VERSION 5.7 ;
  NOWIREEXTENSIONATPIN ON ;
  DIVIDERCHAR "/" ;
  BUSBITCHARS "[]" ;
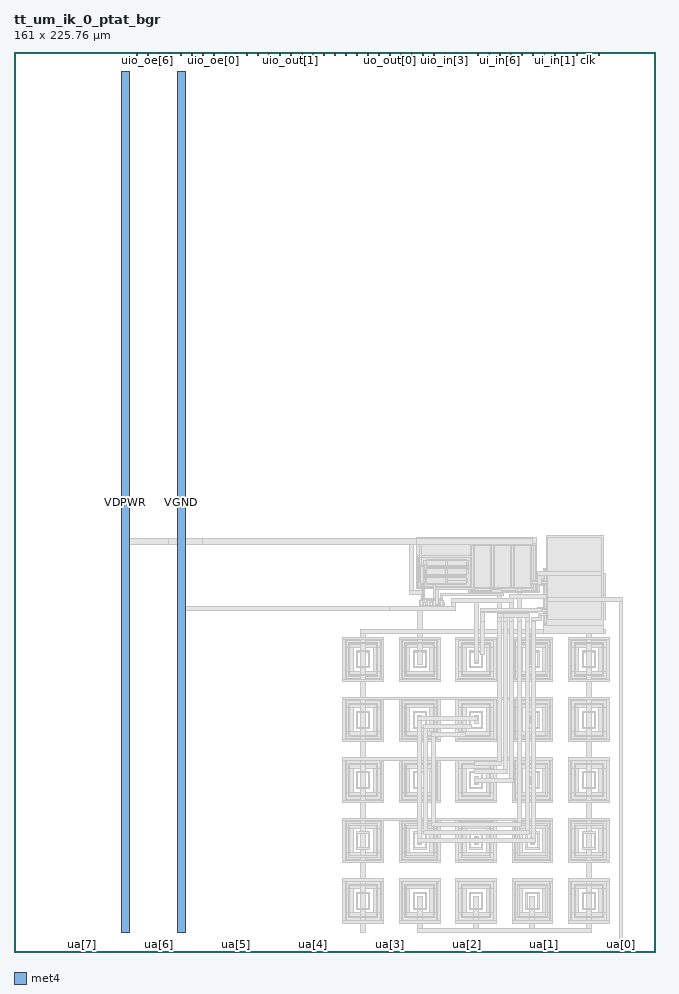
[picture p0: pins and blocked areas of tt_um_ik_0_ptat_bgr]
MACRO tt_um_ik_0_ptat_bgr
  CLASS BLOCK ;
  FOREIGN tt_um_ik_0_ptat_bgr ;
  ORIGIN 0.000 0.000 ;
  SIZE 161.000 BY 225.760 ;
  PIN clk
    DIRECTION INPUT ;
    USE SIGNAL ;
    PORT
      LAYER met4 ;
        RECT 143.830 224.760 144.130 225.760 ;
    END
  END clk
  PIN ena
    DIRECTION INPUT ;
    USE SIGNAL ;
    PORT
      LAYER met4 ;
        RECT 146.590 224.760 146.890 225.760 ;
    END
  END ena
  PIN rst_n
    DIRECTION INPUT ;
    USE SIGNAL ;
    PORT
      LAYER met4 ;
        RECT 141.070 224.760 141.370 225.760 ;
    END
  END rst_n
  PIN ua[0]
    DIRECTION INOUT ;
    USE SIGNAL ;
    ANTENNAGATEAREA 0.500000 ;
    ANTENNADIFFAREA 2.900000 ;
    PORT
      LAYER met4 ;
        RECT 151.810 0.000 152.710 1.000 ;
    END
  END ua[0]
  PIN ua[1]
    DIRECTION INOUT ;
    USE SIGNAL ;
    PORT
      LAYER met4 ;
        RECT 132.490 0.000 133.390 1.000 ;
    END
  END ua[1]
  PIN ua[2]
    DIRECTION INOUT ;
    USE SIGNAL ;
    PORT
      LAYER met4 ;
        RECT 113.170 0.000 114.070 1.000 ;
    END
  END ua[2]
  PIN ua[3]
    DIRECTION INOUT ;
    USE SIGNAL ;
    PORT
      LAYER met4 ;
        RECT 93.850 0.000 94.750 1.000 ;
    END
  END ua[3]
  PIN ua[4]
    DIRECTION INOUT ;
    USE SIGNAL ;
    PORT
      LAYER met4 ;
        RECT 74.530 0.000 75.430 1.000 ;
    END
  END ua[4]
  PIN ua[5]
    DIRECTION INOUT ;
    USE SIGNAL ;
    PORT
      LAYER met4 ;
        RECT 55.210 0.000 56.110 1.000 ;
    END
  END ua[5]
  PIN ua[6]
    DIRECTION INOUT ;
    USE SIGNAL ;
    PORT
      LAYER met4 ;
        RECT 35.890 0.000 36.790 1.000 ;
    END
  END ua[6]
  PIN ua[7]
    DIRECTION INOUT ;
    USE SIGNAL ;
    PORT
      LAYER met4 ;
        RECT 16.570 0.000 17.470 1.000 ;
    END
  END ua[7]
  PIN ui_in[0]
    DIRECTION INPUT ;
    USE SIGNAL ;
    PORT
      LAYER met4 ;
        RECT 138.310 224.760 138.610 225.760 ;
    END
  END ui_in[0]
  PIN ui_in[1]
    DIRECTION INPUT ;
    USE SIGNAL ;
    PORT
      LAYER met4 ;
        RECT 135.550 224.760 135.850 225.760 ;
    END
  END ui_in[1]
  PIN ui_in[2]
    DIRECTION INPUT ;
    USE SIGNAL ;
    PORT
      LAYER met4 ;
        RECT 132.790 224.760 133.090 225.760 ;
    END
  END ui_in[2]
  PIN ui_in[3]
    DIRECTION INPUT ;
    USE SIGNAL ;
    PORT
      LAYER met4 ;
        RECT 130.030 224.760 130.330 225.760 ;
    END
  END ui_in[3]
  PIN ui_in[4]
    DIRECTION INPUT ;
    USE SIGNAL ;
    PORT
      LAYER met4 ;
        RECT 127.270 224.760 127.570 225.760 ;
    END
  END ui_in[4]
  PIN ui_in[5]
    DIRECTION INPUT ;
    USE SIGNAL ;
    PORT
      LAYER met4 ;
        RECT 124.510 224.760 124.810 225.760 ;
    END
  END ui_in[5]
  PIN ui_in[6]
    DIRECTION INPUT ;
    USE SIGNAL ;
    PORT
      LAYER met4 ;
        RECT 121.750 224.760 122.050 225.760 ;
    END
  END ui_in[6]
  PIN ui_in[7]
    DIRECTION INPUT ;
    USE SIGNAL ;
    PORT
      LAYER met4 ;
        RECT 118.990 224.760 119.290 225.760 ;
    END
  END ui_in[7]
  PIN uio_in[0]
    DIRECTION INPUT ;
    USE SIGNAL ;
    PORT
      LAYER met4 ;
        RECT 116.230 224.760 116.530 225.760 ;
    END
  END uio_in[0]
  PIN uio_in[1]
    DIRECTION INPUT ;
    USE SIGNAL ;
    PORT
      LAYER met4 ;
        RECT 113.470 224.760 113.770 225.760 ;
    END
  END uio_in[1]
  PIN uio_in[2]
    DIRECTION INPUT ;
    USE SIGNAL ;
    PORT
      LAYER met4 ;
        RECT 110.710 224.760 111.010 225.760 ;
    END
  END uio_in[2]
  PIN uio_in[3]
    DIRECTION INPUT ;
    USE SIGNAL ;
    PORT
      LAYER met4 ;
        RECT 107.950 224.760 108.250 225.760 ;
    END
  END uio_in[3]
  PIN uio_in[4]
    DIRECTION INPUT ;
    USE SIGNAL ;
    PORT
      LAYER met4 ;
        RECT 105.190 224.760 105.490 225.760 ;
    END
  END uio_in[4]
  PIN uio_in[5]
    DIRECTION INPUT ;
    USE SIGNAL ;
    PORT
      LAYER met4 ;
        RECT 102.430 224.760 102.730 225.760 ;
    END
  END uio_in[5]
  PIN uio_in[6]
    DIRECTION INPUT ;
    USE SIGNAL ;
    PORT
      LAYER met4 ;
        RECT 99.670 224.760 99.970 225.760 ;
    END
  END uio_in[6]
  PIN uio_in[7]
    DIRECTION INPUT ;
    USE SIGNAL ;
    PORT
      LAYER met4 ;
        RECT 96.910 224.760 97.210 225.760 ;
    END
  END uio_in[7]
  PIN uio_oe[0]
    DIRECTION OUTPUT ;
    USE SIGNAL ;
    PORT
      LAYER met4 ;
        RECT 49.990 224.760 50.290 225.760 ;
    END
  END uio_oe[0]
  PIN uio_oe[1]
    DIRECTION OUTPUT ;
    USE SIGNAL ;
    PORT
      LAYER met4 ;
        RECT 47.230 224.760 47.530 225.760 ;
    END
  END uio_oe[1]
  PIN uio_oe[2]
    DIRECTION OUTPUT ;
    USE SIGNAL ;
    PORT
      LAYER met4 ;
        RECT 44.470 224.760 44.770 225.760 ;
    END
  END uio_oe[2]
  PIN uio_oe[3]
    DIRECTION OUTPUT ;
    USE SIGNAL ;
    PORT
      LAYER met4 ;
        RECT 41.710 224.760 42.010 225.760 ;
    END
  END uio_oe[3]
  PIN uio_oe[4]
    DIRECTION OUTPUT ;
    USE SIGNAL ;
    PORT
      LAYER met4 ;
        RECT 38.950 224.760 39.250 225.760 ;
    END
  END uio_oe[4]
  PIN uio_oe[5]
    DIRECTION OUTPUT ;
    USE SIGNAL ;
    PORT
      LAYER met4 ;
        RECT 36.190 224.760 36.490 225.760 ;
    END
  END uio_oe[5]
  PIN uio_oe[6]
    DIRECTION OUTPUT ;
    USE SIGNAL ;
    PORT
      LAYER met4 ;
        RECT 33.430 224.760 33.730 225.760 ;
    END
  END uio_oe[6]
  PIN uio_oe[7]
    DIRECTION OUTPUT ;
    USE SIGNAL ;
    PORT
      LAYER met4 ;
        RECT 30.670 224.760 30.970 225.760 ;
    END
  END uio_oe[7]
  PIN uio_out[0]
    DIRECTION OUTPUT ;
    USE SIGNAL ;
    PORT
      LAYER met4 ;
        RECT 72.070 224.760 72.370 225.760 ;
    END
  END uio_out[0]
  PIN uio_out[1]
    DIRECTION OUTPUT ;
    USE SIGNAL ;
    PORT
      LAYER met4 ;
        RECT 69.310 224.760 69.610 225.760 ;
    END
  END uio_out[1]
  PIN uio_out[2]
    DIRECTION OUTPUT ;
    USE SIGNAL ;
    PORT
      LAYER met4 ;
        RECT 66.550 224.760 66.850 225.760 ;
    END
  END uio_out[2]
  PIN uio_out[3]
    DIRECTION OUTPUT ;
    USE SIGNAL ;
    PORT
      LAYER met4 ;
        RECT 63.790 224.760 64.090 225.760 ;
    END
  END uio_out[3]
  PIN uio_out[4]
    DIRECTION OUTPUT ;
    USE SIGNAL ;
    PORT
      LAYER met4 ;
        RECT 61.030 224.760 61.330 225.760 ;
    END
  END uio_out[4]
  PIN uio_out[5]
    DIRECTION OUTPUT ;
    USE SIGNAL ;
    PORT
      LAYER met4 ;
        RECT 58.270 224.760 58.570 225.760 ;
    END
  END uio_out[5]
  PIN uio_out[6]
    DIRECTION OUTPUT ;
    USE SIGNAL ;
    PORT
      LAYER met4 ;
        RECT 55.510 224.760 55.810 225.760 ;
    END
  END uio_out[6]
  PIN uio_out[7]
    DIRECTION OUTPUT ;
    USE SIGNAL ;
    PORT
      LAYER met4 ;
        RECT 52.750 224.760 53.050 225.760 ;
    END
  END uio_out[7]
  PIN uo_out[0]
    DIRECTION OUTPUT ;
    USE SIGNAL ;
    PORT
      LAYER met4 ;
        RECT 94.150 224.760 94.450 225.760 ;
    END
  END uo_out[0]
  PIN uo_out[1]
    DIRECTION OUTPUT ;
    USE SIGNAL ;
    PORT
      LAYER met4 ;
        RECT 91.390 224.760 91.690 225.760 ;
    END
  END uo_out[1]
  PIN uo_out[2]
    DIRECTION OUTPUT ;
    USE SIGNAL ;
    PORT
      LAYER met4 ;
        RECT 88.630 224.760 88.930 225.760 ;
    END
  END uo_out[2]
  PIN uo_out[3]
    DIRECTION OUTPUT ;
    USE SIGNAL ;
    PORT
      LAYER met4 ;
        RECT 85.870 224.760 86.170 225.760 ;
    END
  END uo_out[3]
  PIN uo_out[4]
    DIRECTION OUTPUT ;
    USE SIGNAL ;
    PORT
      LAYER met4 ;
        RECT 83.110 224.760 83.410 225.760 ;
    END
  END uo_out[4]
  PIN uo_out[5]
    DIRECTION OUTPUT ;
    USE SIGNAL ;
    PORT
      LAYER met4 ;
        RECT 80.350 224.760 80.650 225.760 ;
    END
  END uo_out[5]
  PIN uo_out[6]
    DIRECTION OUTPUT ;
    USE SIGNAL ;
    PORT
      LAYER met4 ;
        RECT 77.590 224.760 77.890 225.760 ;
    END
  END uo_out[6]
  PIN uo_out[7]
    DIRECTION OUTPUT ;
    USE SIGNAL ;
    PORT
      LAYER met4 ;
        RECT 74.830 224.760 75.130 225.760 ;
    END
  END uo_out[7]
  PIN VDPWR
    DIRECTION INOUT ;
    USE POWER ;
    PORT
      LAYER met4 ;
        RECT 27.000 5.000 29.000 220.760 ;
    END
  END VDPWR
  PIN VGND
    DIRECTION INOUT ;
    USE GROUND ;
    PORT
      LAYER met4 ;
        RECT 41.000 5.000 43.000 220.760 ;
    END
  END VGND
  OBS
      LAYER nwell ;
        RECT 100.900 91.100 131.100 104.100 ;
        RECT 114.100 90.100 131.100 91.100 ;
      LAYER pwell ;
        RECT 132.700 85.000 146.700 96.200 ;
        RECT 131.500 84.300 146.700 85.000 ;
        RECT 132.700 82.100 146.700 84.300 ;
      LAYER nwell ;
        RECT 83.300 76.420 91.920 78.220 ;
        RECT 83.300 70.400 85.100 76.420 ;
        RECT 90.120 70.400 91.920 76.420 ;
        RECT 83.300 68.600 91.920 70.400 ;
        RECT 97.450 76.420 106.070 78.220 ;
        RECT 97.450 70.400 99.250 76.420 ;
        RECT 104.270 70.400 106.070 76.420 ;
        RECT 97.450 68.600 106.070 70.400 ;
        RECT 111.600 76.420 120.220 78.220 ;
        RECT 111.600 70.400 113.400 76.420 ;
        RECT 118.420 70.400 120.220 76.420 ;
        RECT 111.600 68.600 120.220 70.400 ;
        RECT 125.750 76.420 134.370 78.220 ;
        RECT 125.750 70.400 127.550 76.420 ;
        RECT 132.570 70.400 134.370 76.420 ;
        RECT 125.750 68.600 134.370 70.400 ;
        RECT 139.900 76.420 148.520 78.220 ;
        RECT 139.900 70.400 141.700 76.420 ;
        RECT 146.720 70.400 148.520 76.420 ;
        RECT 139.900 68.600 148.520 70.400 ;
        RECT 83.300 61.270 91.920 63.070 ;
        RECT 83.300 55.250 85.100 61.270 ;
        RECT 90.120 55.250 91.920 61.270 ;
        RECT 83.300 53.450 91.920 55.250 ;
        RECT 97.450 61.270 106.070 63.070 ;
        RECT 97.450 55.250 99.250 61.270 ;
        RECT 104.270 55.250 106.070 61.270 ;
        RECT 97.450 53.450 106.070 55.250 ;
        RECT 111.600 61.270 120.220 63.070 ;
        RECT 111.600 55.250 113.400 61.270 ;
        RECT 118.420 55.250 120.220 61.270 ;
        RECT 111.600 53.450 120.220 55.250 ;
        RECT 125.750 61.270 134.370 63.070 ;
        RECT 125.750 55.250 127.550 61.270 ;
        RECT 132.570 55.250 134.370 61.270 ;
        RECT 125.750 53.450 134.370 55.250 ;
        RECT 139.900 61.270 148.520 63.070 ;
        RECT 139.900 55.250 141.700 61.270 ;
        RECT 146.720 55.250 148.520 61.270 ;
        RECT 139.900 53.450 148.520 55.250 ;
        RECT 83.300 46.120 91.920 47.920 ;
        RECT 83.300 40.100 85.100 46.120 ;
        RECT 90.120 40.100 91.920 46.120 ;
        RECT 83.300 38.300 91.920 40.100 ;
        RECT 97.450 46.120 106.070 47.920 ;
        RECT 97.450 40.100 99.250 46.120 ;
        RECT 104.270 40.100 106.070 46.120 ;
        RECT 97.450 38.300 106.070 40.100 ;
        RECT 111.600 46.120 120.220 47.920 ;
        RECT 111.600 40.100 113.400 46.120 ;
        RECT 118.420 40.100 120.220 46.120 ;
        RECT 111.600 38.300 120.220 40.100 ;
        RECT 125.750 46.120 134.370 47.920 ;
        RECT 125.750 40.100 127.550 46.120 ;
        RECT 132.570 40.100 134.370 46.120 ;
        RECT 125.750 38.300 134.370 40.100 ;
        RECT 139.900 46.120 148.520 47.920 ;
        RECT 139.900 40.100 141.700 46.120 ;
        RECT 146.720 40.100 148.520 46.120 ;
        RECT 139.900 38.300 148.520 40.100 ;
        RECT 83.300 30.970 91.920 32.770 ;
        RECT 83.300 24.950 85.100 30.970 ;
        RECT 90.120 24.950 91.920 30.970 ;
        RECT 83.300 23.150 91.920 24.950 ;
        RECT 97.450 30.970 106.070 32.770 ;
        RECT 97.450 24.950 99.250 30.970 ;
        RECT 104.270 24.950 106.070 30.970 ;
        RECT 97.450 23.150 106.070 24.950 ;
        RECT 111.600 30.970 120.220 32.770 ;
        RECT 111.600 24.950 113.400 30.970 ;
        RECT 118.420 24.950 120.220 30.970 ;
        RECT 111.600 23.150 120.220 24.950 ;
        RECT 125.750 30.970 134.370 32.770 ;
        RECT 125.750 24.950 127.550 30.970 ;
        RECT 132.570 24.950 134.370 30.970 ;
        RECT 125.750 23.150 134.370 24.950 ;
        RECT 139.900 30.970 148.520 32.770 ;
        RECT 139.900 24.950 141.700 30.970 ;
        RECT 146.720 24.950 148.520 30.970 ;
        RECT 139.900 23.150 148.520 24.950 ;
        RECT 83.300 15.820 91.920 17.620 ;
        RECT 83.300 9.800 85.100 15.820 ;
        RECT 90.120 9.800 91.920 15.820 ;
        RECT 83.300 8.000 91.920 9.800 ;
        RECT 97.450 15.820 106.070 17.620 ;
        RECT 97.450 9.800 99.250 15.820 ;
        RECT 104.270 9.800 106.070 15.820 ;
        RECT 97.450 8.000 106.070 9.800 ;
        RECT 111.600 15.820 120.220 17.620 ;
        RECT 111.600 9.800 113.400 15.820 ;
        RECT 118.420 9.800 120.220 15.820 ;
        RECT 111.600 8.000 120.220 9.800 ;
        RECT 125.750 15.820 134.370 17.620 ;
        RECT 125.750 9.800 127.550 15.820 ;
        RECT 132.570 9.800 134.370 15.820 ;
        RECT 125.750 8.000 134.370 9.800 ;
        RECT 139.900 15.820 148.520 17.620 ;
        RECT 139.900 9.800 141.700 15.820 ;
        RECT 146.720 9.800 148.520 15.820 ;
        RECT 139.900 8.000 148.520 9.800 ;
      LAYER li1 ;
        RECT 114.400 102.000 130.800 102.400 ;
        RECT 114.400 99.400 114.800 102.000 ;
        RECT 101.100 99.000 114.800 99.400 ;
        RECT 101.100 91.800 101.500 99.000 ;
        RECT 103.570 98.335 113.570 98.505 ;
        RECT 101.940 97.080 102.110 98.120 ;
        RECT 102.730 97.080 102.900 98.120 ;
        RECT 103.340 97.080 103.510 98.120 ;
        RECT 113.630 97.080 113.800 98.120 ;
        RECT 102.170 96.695 102.670 96.865 ;
        RECT 103.570 96.695 113.570 96.865 ;
        RECT 103.570 96.135 113.570 96.305 ;
        RECT 103.340 94.880 103.510 95.920 ;
        RECT 113.630 94.880 113.800 95.920 ;
        RECT 103.570 94.495 113.570 94.665 ;
        RECT 103.570 93.935 113.570 94.105 ;
        RECT 101.840 92.680 102.010 93.720 ;
        RECT 102.630 92.680 102.800 93.720 ;
        RECT 103.340 92.680 103.510 93.720 ;
        RECT 113.630 92.680 113.800 93.720 ;
        RECT 102.070 92.295 102.570 92.465 ;
        RECT 103.570 92.295 113.570 92.465 ;
        RECT 114.400 91.800 114.800 99.000 ;
        RECT 101.100 91.400 114.800 91.800 ;
        RECT 115.340 91.580 115.510 101.620 ;
        RECT 119.630 91.580 119.800 101.620 ;
        RECT 120.340 91.580 120.510 101.620 ;
        RECT 124.630 91.580 124.800 101.620 ;
        RECT 125.340 91.580 125.510 101.620 ;
        RECT 129.630 91.580 129.800 101.620 ;
        RECT 114.400 90.800 114.800 91.400 ;
        RECT 115.570 91.195 119.570 91.365 ;
        RECT 120.570 91.195 124.570 91.365 ;
        RECT 125.570 91.195 129.570 91.365 ;
        RECT 130.400 90.800 130.800 102.000 ;
        RECT 114.400 90.400 130.800 90.800 ;
        RECT 132.900 95.800 146.500 96.000 ;
        RECT 132.900 89.600 133.100 95.800 ;
        RECT 133.640 94.310 135.800 95.000 ;
        RECT 143.640 94.310 145.800 95.000 ;
        RECT 133.640 93.310 135.800 94.000 ;
        RECT 143.640 93.310 145.800 94.000 ;
        RECT 133.640 92.310 135.800 93.000 ;
        RECT 143.640 92.310 145.800 93.000 ;
        RECT 133.640 91.310 135.800 92.000 ;
        RECT 143.640 91.310 145.800 92.000 ;
        RECT 133.640 90.310 135.800 91.000 ;
        RECT 143.640 90.310 145.800 91.000 ;
        RECT 132.500 88.800 133.100 89.600 ;
        RECT 133.640 89.310 135.800 90.000 ;
        RECT 143.640 89.310 145.800 90.000 ;
        RECT 102.040 88.320 102.540 88.490 ;
        RECT 103.690 88.320 104.190 88.490 ;
        RECT 105.340 88.320 105.840 88.490 ;
        RECT 106.990 88.320 107.490 88.490 ;
        RECT 101.810 87.110 101.980 88.150 ;
        RECT 102.600 87.110 102.770 88.150 ;
        RECT 103.460 87.110 103.630 88.150 ;
        RECT 104.250 87.110 104.420 88.150 ;
        RECT 105.110 87.110 105.280 88.150 ;
        RECT 105.900 87.110 106.070 88.150 ;
        RECT 106.760 87.110 106.930 88.150 ;
        RECT 107.550 87.110 107.720 88.150 ;
        RECT 124.300 86.600 125.300 87.600 ;
        RECT 132.900 82.500 133.100 88.800 ;
        RECT 133.640 88.310 135.800 89.000 ;
        RECT 143.640 88.310 145.800 89.000 ;
        RECT 133.640 87.310 135.800 88.000 ;
        RECT 143.640 87.310 145.800 88.000 ;
        RECT 133.640 86.310 135.800 87.000 ;
        RECT 143.640 86.310 145.800 87.000 ;
        RECT 133.640 85.310 135.800 86.000 ;
        RECT 143.640 85.310 145.800 86.000 ;
        RECT 133.640 84.310 135.800 85.000 ;
        RECT 143.640 84.310 145.800 85.000 ;
        RECT 133.640 83.310 135.800 84.000 ;
        RECT 143.640 83.310 145.800 84.000 ;
        RECT 146.300 82.500 146.500 95.800 ;
        RECT 132.900 82.300 146.500 82.500 ;
        RECT 143.700 80.850 144.700 82.300 ;
        RECT 82.500 78.400 92.700 79.000 ;
        RECT 82.500 68.400 83.100 78.400 ;
        RECT 83.930 77.260 91.290 77.590 ;
        RECT 83.930 69.560 84.260 77.260 ;
        RECT 85.940 75.250 89.280 75.580 ;
        RECT 85.940 71.570 86.270 75.250 ;
        RECT 87.105 72.395 88.115 74.425 ;
        RECT 88.950 71.570 89.280 75.250 ;
        RECT 85.940 71.240 89.280 71.570 ;
        RECT 90.960 69.560 91.290 77.260 ;
        RECT 83.930 69.230 91.290 69.560 ;
        RECT 92.100 68.400 92.700 78.400 ;
        RECT 82.500 67.800 92.700 68.400 ;
        RECT 96.700 78.400 106.900 79.000 ;
        RECT 96.700 68.400 97.300 78.400 ;
        RECT 98.080 77.260 105.440 77.590 ;
        RECT 98.080 69.560 98.410 77.260 ;
        RECT 100.090 75.250 103.430 75.580 ;
        RECT 100.090 71.570 100.420 75.250 ;
        RECT 101.255 72.395 102.265 74.425 ;
        RECT 103.100 71.570 103.430 75.250 ;
        RECT 100.090 71.240 103.430 71.570 ;
        RECT 105.110 69.560 105.440 77.260 ;
        RECT 98.080 69.230 105.440 69.560 ;
        RECT 106.300 68.400 106.900 78.400 ;
        RECT 96.700 67.800 106.900 68.400 ;
        RECT 110.800 78.400 121.000 79.000 ;
        RECT 110.800 68.400 111.400 78.400 ;
        RECT 112.230 77.260 119.590 77.590 ;
        RECT 112.230 69.560 112.560 77.260 ;
        RECT 114.240 75.250 117.580 75.580 ;
        RECT 114.240 71.570 114.570 75.250 ;
        RECT 115.405 72.395 116.415 74.425 ;
        RECT 117.250 71.570 117.580 75.250 ;
        RECT 114.240 71.240 117.580 71.570 ;
        RECT 119.260 69.560 119.590 77.260 ;
        RECT 112.230 69.230 119.590 69.560 ;
        RECT 120.400 68.400 121.000 78.400 ;
        RECT 110.800 67.800 121.000 68.400 ;
        RECT 125.000 78.400 135.200 79.000 ;
        RECT 125.000 68.400 125.600 78.400 ;
        RECT 126.380 77.260 133.740 77.590 ;
        RECT 126.380 69.560 126.710 77.260 ;
        RECT 128.390 75.250 131.730 75.580 ;
        RECT 128.390 71.570 128.720 75.250 ;
        RECT 129.555 72.395 130.565 74.425 ;
        RECT 131.400 71.570 131.730 75.250 ;
        RECT 128.390 71.240 131.730 71.570 ;
        RECT 133.410 69.560 133.740 77.260 ;
        RECT 126.380 69.230 133.740 69.560 ;
        RECT 134.600 68.400 135.200 78.400 ;
        RECT 125.000 67.800 135.200 68.400 ;
        RECT 139.100 78.400 149.300 79.000 ;
        RECT 139.100 68.400 139.700 78.400 ;
        RECT 140.530 77.260 147.890 77.590 ;
        RECT 140.530 69.560 140.860 77.260 ;
        RECT 142.540 75.250 145.880 75.580 ;
        RECT 142.540 71.570 142.870 75.250 ;
        RECT 143.705 72.395 144.715 74.425 ;
        RECT 145.550 71.570 145.880 75.250 ;
        RECT 142.540 71.240 145.880 71.570 ;
        RECT 147.560 69.560 147.890 77.260 ;
        RECT 140.530 69.230 147.890 69.560 ;
        RECT 148.700 68.400 149.300 78.400 ;
        RECT 139.100 67.800 149.300 68.400 ;
        RECT 82.500 63.300 92.700 63.900 ;
        RECT 82.500 53.300 83.100 63.300 ;
        RECT 83.930 62.110 91.290 62.440 ;
        RECT 83.930 54.410 84.260 62.110 ;
        RECT 85.940 60.100 89.280 60.430 ;
        RECT 85.940 56.420 86.270 60.100 ;
        RECT 87.105 57.245 88.115 59.275 ;
        RECT 88.950 56.420 89.280 60.100 ;
        RECT 85.940 56.090 89.280 56.420 ;
        RECT 90.960 54.410 91.290 62.110 ;
        RECT 83.930 54.080 91.290 54.410 ;
        RECT 92.100 53.300 92.700 63.300 ;
        RECT 82.500 52.700 92.700 53.300 ;
        RECT 96.700 63.300 106.900 63.900 ;
        RECT 96.700 53.300 97.300 63.300 ;
        RECT 98.080 62.110 105.440 62.440 ;
        RECT 98.080 54.410 98.410 62.110 ;
        RECT 100.090 60.100 103.430 60.430 ;
        RECT 100.090 56.420 100.420 60.100 ;
        RECT 101.255 57.245 102.265 59.275 ;
        RECT 103.100 56.420 103.430 60.100 ;
        RECT 100.090 56.090 103.430 56.420 ;
        RECT 105.110 54.410 105.440 62.110 ;
        RECT 98.080 54.080 105.440 54.410 ;
        RECT 106.300 53.300 106.900 63.300 ;
        RECT 96.700 52.700 106.900 53.300 ;
        RECT 110.800 63.300 121.000 63.900 ;
        RECT 110.800 53.300 111.400 63.300 ;
        RECT 112.230 62.110 119.590 62.440 ;
        RECT 112.230 54.410 112.560 62.110 ;
        RECT 114.240 60.100 117.580 60.430 ;
        RECT 114.240 56.420 114.570 60.100 ;
        RECT 115.405 57.245 116.415 59.275 ;
        RECT 117.250 56.420 117.580 60.100 ;
        RECT 114.240 56.090 117.580 56.420 ;
        RECT 119.260 54.410 119.590 62.110 ;
        RECT 112.230 54.080 119.590 54.410 ;
        RECT 120.400 53.300 121.000 63.300 ;
        RECT 110.800 52.700 121.000 53.300 ;
        RECT 125.000 63.300 135.200 63.900 ;
        RECT 125.000 53.300 125.600 63.300 ;
        RECT 126.380 62.110 133.740 62.440 ;
        RECT 126.380 54.410 126.710 62.110 ;
        RECT 128.390 60.100 131.730 60.430 ;
        RECT 128.390 56.420 128.720 60.100 ;
        RECT 129.555 57.245 130.565 59.275 ;
        RECT 131.400 56.420 131.730 60.100 ;
        RECT 128.390 56.090 131.730 56.420 ;
        RECT 133.410 54.410 133.740 62.110 ;
        RECT 126.380 54.080 133.740 54.410 ;
        RECT 134.600 53.300 135.200 63.300 ;
        RECT 125.000 52.700 135.200 53.300 ;
        RECT 139.100 63.300 149.300 63.900 ;
        RECT 139.100 53.300 139.700 63.300 ;
        RECT 140.530 62.110 147.890 62.440 ;
        RECT 140.530 54.410 140.860 62.110 ;
        RECT 142.540 60.100 145.880 60.430 ;
        RECT 142.540 56.420 142.870 60.100 ;
        RECT 143.705 57.245 144.715 59.275 ;
        RECT 145.550 56.420 145.880 60.100 ;
        RECT 142.540 56.090 145.880 56.420 ;
        RECT 147.560 54.410 147.890 62.110 ;
        RECT 140.530 54.080 147.890 54.410 ;
        RECT 148.700 53.300 149.300 63.300 ;
        RECT 139.100 52.700 149.300 53.300 ;
        RECT 82.500 48.100 92.700 48.700 ;
        RECT 82.500 38.100 83.100 48.100 ;
        RECT 83.930 46.960 91.290 47.290 ;
        RECT 83.930 39.260 84.260 46.960 ;
        RECT 85.940 44.950 89.280 45.280 ;
        RECT 85.940 41.270 86.270 44.950 ;
        RECT 87.105 42.095 88.115 44.125 ;
        RECT 88.950 41.270 89.280 44.950 ;
        RECT 85.940 40.940 89.280 41.270 ;
        RECT 90.960 39.260 91.290 46.960 ;
        RECT 83.930 38.930 91.290 39.260 ;
        RECT 92.100 38.100 92.700 48.100 ;
        RECT 82.500 37.500 92.700 38.100 ;
        RECT 96.700 48.100 106.900 48.700 ;
        RECT 96.700 38.100 97.300 48.100 ;
        RECT 98.080 46.960 105.440 47.290 ;
        RECT 98.080 39.260 98.410 46.960 ;
        RECT 100.090 44.950 103.430 45.280 ;
        RECT 100.090 41.270 100.420 44.950 ;
        RECT 101.255 42.095 102.265 44.125 ;
        RECT 103.100 41.270 103.430 44.950 ;
        RECT 100.090 40.940 103.430 41.270 ;
        RECT 105.110 39.260 105.440 46.960 ;
        RECT 98.080 38.930 105.440 39.260 ;
        RECT 106.300 38.100 106.900 48.100 ;
        RECT 96.700 37.500 106.900 38.100 ;
        RECT 110.800 48.100 121.000 48.700 ;
        RECT 110.800 38.100 111.400 48.100 ;
        RECT 112.230 46.960 119.590 47.290 ;
        RECT 112.230 39.260 112.560 46.960 ;
        RECT 114.240 44.950 117.580 45.280 ;
        RECT 114.240 41.270 114.570 44.950 ;
        RECT 115.405 42.095 116.415 44.125 ;
        RECT 117.250 41.270 117.580 44.950 ;
        RECT 114.240 40.940 117.580 41.270 ;
        RECT 119.260 39.260 119.590 46.960 ;
        RECT 112.230 38.930 119.590 39.260 ;
        RECT 120.400 38.100 121.000 48.100 ;
        RECT 110.800 37.500 121.000 38.100 ;
        RECT 125.000 48.100 135.200 48.700 ;
        RECT 125.000 38.100 125.600 48.100 ;
        RECT 126.380 46.960 133.740 47.290 ;
        RECT 126.380 39.260 126.710 46.960 ;
        RECT 128.390 44.950 131.730 45.280 ;
        RECT 128.390 41.270 128.720 44.950 ;
        RECT 129.555 42.095 130.565 44.125 ;
        RECT 131.400 41.270 131.730 44.950 ;
        RECT 128.390 40.940 131.730 41.270 ;
        RECT 133.410 39.260 133.740 46.960 ;
        RECT 126.380 38.930 133.740 39.260 ;
        RECT 134.600 38.100 135.200 48.100 ;
        RECT 125.000 37.500 135.200 38.100 ;
        RECT 139.100 48.100 149.300 48.700 ;
        RECT 139.100 38.100 139.700 48.100 ;
        RECT 140.530 46.960 147.890 47.290 ;
        RECT 140.530 39.260 140.860 46.960 ;
        RECT 142.540 44.950 145.880 45.280 ;
        RECT 142.540 41.270 142.870 44.950 ;
        RECT 143.705 42.095 144.715 44.125 ;
        RECT 145.550 41.270 145.880 44.950 ;
        RECT 142.540 40.940 145.880 41.270 ;
        RECT 147.560 39.260 147.890 46.960 ;
        RECT 140.530 38.930 147.890 39.260 ;
        RECT 148.700 38.100 149.300 48.100 ;
        RECT 139.100 37.500 149.300 38.100 ;
        RECT 82.500 33.000 135.200 33.600 ;
        RECT 82.500 23.000 83.100 33.000 ;
        RECT 83.930 31.810 91.290 32.140 ;
        RECT 83.930 24.110 84.260 31.810 ;
        RECT 85.940 29.800 89.280 30.130 ;
        RECT 85.940 26.120 86.270 29.800 ;
        RECT 87.105 26.945 88.115 28.975 ;
        RECT 88.950 26.120 89.280 29.800 ;
        RECT 85.940 25.790 89.280 26.120 ;
        RECT 90.960 24.110 91.290 31.810 ;
        RECT 83.930 23.780 91.290 24.110 ;
        RECT 92.100 23.000 92.700 33.000 ;
        RECT 82.500 22.400 92.700 23.000 ;
        RECT 96.700 23.000 97.300 33.000 ;
        RECT 98.080 31.810 105.440 32.140 ;
        RECT 98.080 24.110 98.410 31.810 ;
        RECT 100.090 29.800 103.430 30.130 ;
        RECT 100.090 26.120 100.420 29.800 ;
        RECT 101.255 26.945 102.265 28.975 ;
        RECT 103.100 26.120 103.430 29.800 ;
        RECT 100.090 25.790 103.430 26.120 ;
        RECT 105.110 24.110 105.440 31.810 ;
        RECT 98.080 23.780 105.440 24.110 ;
        RECT 106.300 23.000 106.900 33.000 ;
        RECT 96.700 22.400 106.900 23.000 ;
        RECT 110.800 23.000 111.400 33.000 ;
        RECT 112.230 31.810 119.590 32.140 ;
        RECT 112.230 24.110 112.560 31.810 ;
        RECT 114.240 29.800 117.580 30.130 ;
        RECT 114.240 26.120 114.570 29.800 ;
        RECT 115.405 26.945 116.415 28.975 ;
        RECT 117.250 26.120 117.580 29.800 ;
        RECT 114.240 25.790 117.580 26.120 ;
        RECT 119.260 24.110 119.590 31.810 ;
        RECT 112.230 23.780 119.590 24.110 ;
        RECT 120.400 23.000 121.000 33.000 ;
        RECT 110.800 22.400 121.000 23.000 ;
        RECT 125.000 23.000 125.600 33.000 ;
        RECT 126.380 31.810 133.740 32.140 ;
        RECT 126.380 24.110 126.710 31.810 ;
        RECT 128.390 29.800 131.730 30.130 ;
        RECT 128.390 26.120 128.720 29.800 ;
        RECT 129.555 26.945 130.565 28.975 ;
        RECT 131.400 26.120 131.730 29.800 ;
        RECT 128.390 25.790 131.730 26.120 ;
        RECT 133.410 24.110 133.740 31.810 ;
        RECT 126.380 23.780 133.740 24.110 ;
        RECT 134.600 23.000 135.200 33.000 ;
        RECT 125.000 22.400 135.200 23.000 ;
        RECT 139.100 33.000 149.300 33.600 ;
        RECT 139.100 23.000 139.700 33.000 ;
        RECT 140.530 31.810 147.890 32.140 ;
        RECT 140.530 24.110 140.860 31.810 ;
        RECT 142.540 29.800 145.880 30.130 ;
        RECT 142.540 26.120 142.870 29.800 ;
        RECT 143.705 26.945 144.715 28.975 ;
        RECT 145.550 26.120 145.880 29.800 ;
        RECT 142.540 25.790 145.880 26.120 ;
        RECT 147.560 24.110 147.890 31.810 ;
        RECT 140.530 23.780 147.890 24.110 ;
        RECT 148.700 23.000 149.300 33.000 ;
        RECT 139.100 22.400 149.300 23.000 ;
        RECT 82.500 17.800 92.700 18.400 ;
        RECT 82.500 7.800 83.100 17.800 ;
        RECT 83.930 16.660 91.290 16.990 ;
        RECT 83.930 8.960 84.260 16.660 ;
        RECT 85.940 14.650 89.280 14.980 ;
        RECT 85.940 10.970 86.270 14.650 ;
        RECT 87.105 11.795 88.115 13.825 ;
        RECT 88.950 10.970 89.280 14.650 ;
        RECT 85.940 10.640 89.280 10.970 ;
        RECT 90.960 8.960 91.290 16.660 ;
        RECT 83.930 8.630 91.290 8.960 ;
        RECT 92.100 7.800 92.700 17.800 ;
        RECT 82.500 7.200 92.700 7.800 ;
        RECT 96.700 17.800 106.900 18.400 ;
        RECT 96.700 7.800 97.300 17.800 ;
        RECT 98.080 16.660 105.440 16.990 ;
        RECT 98.080 8.960 98.410 16.660 ;
        RECT 100.090 14.650 103.430 14.980 ;
        RECT 100.090 10.970 100.420 14.650 ;
        RECT 101.255 11.795 102.265 13.825 ;
        RECT 103.100 10.970 103.430 14.650 ;
        RECT 100.090 10.640 103.430 10.970 ;
        RECT 105.110 8.960 105.440 16.660 ;
        RECT 98.080 8.630 105.440 8.960 ;
        RECT 106.300 7.800 106.900 17.800 ;
        RECT 96.700 7.200 106.900 7.800 ;
        RECT 110.800 17.800 121.000 18.400 ;
        RECT 110.800 7.800 111.400 17.800 ;
        RECT 112.230 16.660 119.590 16.990 ;
        RECT 112.230 8.960 112.560 16.660 ;
        RECT 114.240 14.650 117.580 14.980 ;
        RECT 114.240 10.970 114.570 14.650 ;
        RECT 115.405 11.795 116.415 13.825 ;
        RECT 117.250 10.970 117.580 14.650 ;
        RECT 114.240 10.640 117.580 10.970 ;
        RECT 119.260 8.960 119.590 16.660 ;
        RECT 112.230 8.630 119.590 8.960 ;
        RECT 120.400 7.800 121.000 17.800 ;
        RECT 110.800 7.200 121.000 7.800 ;
        RECT 125.000 17.800 135.200 18.400 ;
        RECT 125.000 7.800 125.600 17.800 ;
        RECT 126.380 16.660 133.740 16.990 ;
        RECT 126.380 8.960 126.710 16.660 ;
        RECT 128.390 14.650 131.730 14.980 ;
        RECT 128.390 10.970 128.720 14.650 ;
        RECT 129.555 11.795 130.565 13.825 ;
        RECT 131.400 10.970 131.730 14.650 ;
        RECT 128.390 10.640 131.730 10.970 ;
        RECT 133.410 8.960 133.740 16.660 ;
        RECT 126.380 8.630 133.740 8.960 ;
        RECT 134.600 7.800 135.200 17.800 ;
        RECT 125.000 7.200 135.200 7.800 ;
        RECT 139.100 17.800 149.300 18.400 ;
        RECT 139.100 7.800 139.700 17.800 ;
        RECT 140.530 16.660 147.890 16.990 ;
        RECT 140.530 8.960 140.860 16.660 ;
        RECT 142.540 14.650 145.880 14.980 ;
        RECT 142.540 10.970 142.870 14.650 ;
        RECT 143.705 11.795 144.715 13.825 ;
        RECT 145.550 10.970 145.880 14.650 ;
        RECT 142.540 10.640 145.880 10.970 ;
        RECT 147.560 8.960 147.890 16.660 ;
        RECT 140.530 8.630 147.890 8.960 ;
        RECT 148.700 7.800 149.300 17.800 ;
        RECT 139.100 7.200 149.300 7.800 ;
        RECT 87.000 5.000 88.200 6.100 ;
      LAYER met1 ;
        RECT 99.300 102.100 130.100 103.600 ;
        RECT 99.300 90.700 100.300 102.100 ;
        RECT 101.700 98.900 102.250 102.100 ;
        RECT 115.100 102.000 130.100 102.100 ;
        RECT 101.800 97.100 102.150 98.900 ;
        RECT 103.590 98.305 113.550 98.535 ;
        RECT 102.700 97.100 103.540 98.100 ;
        RECT 101.800 93.700 102.000 97.100 ;
        RECT 108.300 96.895 108.800 98.305 ;
        RECT 113.600 97.100 114.100 98.100 ;
        RECT 102.190 96.850 102.650 96.895 ;
        RECT 102.190 96.665 102.850 96.850 ;
        RECT 103.590 96.665 113.550 96.895 ;
        RECT 101.800 93.650 102.040 93.700 ;
        RECT 101.810 92.700 102.040 93.650 ;
        RECT 102.600 93.400 102.850 96.665 ;
        RECT 108.300 96.335 108.800 96.665 ;
        RECT 103.590 96.105 113.550 96.335 ;
        RECT 103.100 94.900 103.540 95.900 ;
        RECT 103.100 93.700 103.400 94.900 ;
        RECT 108.300 94.695 108.800 96.105 ;
        RECT 113.800 95.900 114.100 97.100 ;
        RECT 113.600 94.900 114.100 95.900 ;
        RECT 103.590 94.465 113.550 94.695 ;
        RECT 108.300 94.135 108.800 94.465 ;
        RECT 103.590 93.905 113.550 94.135 ;
        RECT 102.600 93.000 102.830 93.400 ;
        RECT 102.600 92.700 102.950 93.000 ;
        RECT 103.100 92.700 103.540 93.700 ;
        RECT 108.300 93.300 108.800 93.905 ;
        RECT 113.600 93.300 113.830 93.700 ;
        RECT 108.300 93.100 113.830 93.300 ;
        RECT 102.090 92.265 102.550 92.495 ;
        RECT 102.100 90.700 102.350 92.265 ;
        RECT 99.300 89.700 102.350 90.700 ;
        RECT 102.100 88.520 102.350 89.700 ;
        RECT 102.750 88.550 102.950 92.700 ;
        RECT 108.300 92.495 108.800 93.100 ;
        RECT 113.600 92.700 113.830 93.100 ;
        RECT 103.590 92.265 113.550 92.495 ;
        RECT 105.310 88.550 105.790 92.265 ;
        RECT 115.200 91.550 115.600 102.000 ;
        RECT 119.500 91.550 119.900 101.650 ;
        RECT 120.200 91.550 120.600 102.000 ;
        RECT 124.500 91.400 124.900 101.650 ;
        RECT 125.200 91.550 125.600 102.000 ;
        RECT 129.500 93.300 129.900 101.650 ;
        RECT 131.300 94.350 132.300 95.350 ;
        RECT 133.650 94.250 148.250 94.950 ;
        RECT 131.300 93.300 132.700 93.400 ;
        RECT 133.650 93.350 135.800 94.250 ;
        RECT 143.650 93.350 148.250 94.250 ;
        RECT 129.500 93.000 132.700 93.300 ;
        RECT 129.500 92.950 133.700 93.000 ;
        RECT 129.500 92.360 135.775 92.950 ;
        RECT 143.665 92.360 145.770 92.950 ;
        RECT 129.500 92.300 133.700 92.360 ;
        RECT 129.500 91.550 129.900 92.300 ;
        RECT 131.300 92.000 132.700 92.300 ;
        RECT 144.500 91.950 145.500 92.360 ;
        RECT 114.850 91.100 130.100 91.400 ;
        RECT 133.670 91.360 135.775 91.950 ;
        RECT 143.665 91.360 145.770 91.950 ;
        RECT 114.850 90.850 115.450 91.100 ;
        RECT 119.500 90.300 122.300 90.950 ;
        RECT 102.750 88.520 104.150 88.550 ;
        RECT 102.060 88.290 102.520 88.520 ;
        RECT 102.750 88.300 104.170 88.520 ;
        RECT 102.750 88.130 102.950 88.300 ;
        RECT 103.710 88.290 104.170 88.300 ;
        RECT 104.400 88.300 106.850 88.550 ;
        RECT 107.050 88.520 107.450 89.100 ;
        RECT 104.400 88.150 104.650 88.300 ;
        RECT 105.360 88.290 105.820 88.300 ;
        RECT 104.250 88.130 104.650 88.150 ;
        RECT 106.600 88.130 106.850 88.300 ;
        RECT 107.010 88.290 107.470 88.520 ;
        RECT 101.780 87.550 102.010 88.130 ;
        RECT 101.650 87.130 102.010 87.550 ;
        RECT 102.570 87.700 102.950 88.130 ;
        RECT 102.570 87.130 102.800 87.700 ;
        RECT 103.430 87.550 103.660 88.130 ;
        RECT 103.300 87.130 103.660 87.550 ;
        RECT 104.220 87.700 104.650 88.130 ;
        RECT 104.220 87.130 104.450 87.700 ;
        RECT 105.080 87.550 105.310 88.130 ;
        RECT 104.950 87.130 105.310 87.550 ;
        RECT 105.870 88.100 106.100 88.130 ;
        RECT 105.870 87.200 106.400 88.100 ;
        RECT 106.600 87.700 106.960 88.130 ;
        RECT 105.870 87.130 106.100 87.200 ;
        RECT 106.730 87.130 106.960 87.700 ;
        RECT 107.520 87.550 107.750 88.130 ;
        RECT 107.520 87.130 107.900 87.550 ;
        RECT 101.650 86.850 101.900 87.130 ;
        RECT 103.300 86.850 103.550 87.130 ;
        RECT 104.950 86.850 105.200 87.130 ;
        RECT 107.650 86.850 107.900 87.130 ;
        RECT 101.650 86.700 107.900 86.850 ;
        RECT 93.000 85.700 107.900 86.700 ;
        RECT 101.100 81.000 102.350 85.700 ;
        RECT 117.100 81.800 118.100 86.100 ;
        RECT 121.300 84.800 122.300 90.300 ;
        RECT 121.300 83.800 123.800 84.800 ;
        RECT 121.300 81.800 122.300 83.800 ;
        RECT 122.800 81.800 123.800 83.800 ;
        RECT 124.300 81.800 125.300 89.700 ;
        RECT 126.300 81.800 127.300 91.100 ;
        RECT 134.000 90.950 135.000 91.360 ;
        RECT 133.670 90.360 135.775 90.950 ;
        RECT 143.665 90.360 145.770 90.950 ;
        RECT 144.500 89.950 145.500 90.360 ;
        RECT 131.300 88.700 133.100 89.700 ;
        RECT 133.670 89.360 135.775 89.950 ;
        RECT 143.665 89.360 145.770 89.950 ;
        RECT 134.000 88.950 135.000 89.360 ;
        RECT 133.670 88.360 135.775 88.950 ;
        RECT 143.665 88.360 145.770 88.950 ;
        RECT 144.500 87.950 145.500 88.360 ;
        RECT 133.670 87.360 135.775 87.950 ;
        RECT 143.665 87.360 145.770 87.950 ;
        RECT 134.000 86.950 135.000 87.360 ;
        RECT 133.670 86.360 135.775 86.950 ;
        RECT 143.665 86.360 145.770 86.950 ;
        RECT 131.200 86.100 132.700 86.300 ;
        RECT 131.200 85.950 133.700 86.100 ;
        RECT 144.500 85.950 145.500 86.360 ;
        RECT 131.200 85.360 135.775 85.950 ;
        RECT 143.665 85.360 145.770 85.950 ;
        RECT 131.200 85.300 133.700 85.360 ;
        RECT 131.500 84.950 133.700 85.000 ;
        RECT 128.300 81.800 129.300 84.800 ;
        RECT 131.500 84.360 135.775 84.950 ;
        RECT 131.500 84.300 133.700 84.360 ;
        RECT 131.500 83.800 132.200 84.300 ;
        RECT 143.650 84.000 148.250 85.000 ;
        RECT 129.800 83.100 132.200 83.800 ;
        RECT 133.600 83.300 148.250 84.000 ;
        RECT 129.800 81.800 130.800 83.100 ;
        RECT 87.000 80.000 148.250 81.000 ;
        RECT 87.000 79.000 88.200 80.000 ;
        RECT 101.100 79.000 102.350 80.000 ;
        RECT 129.500 79.000 130.700 80.000 ;
        RECT 143.590 79.990 144.800 80.000 ;
        RECT 143.600 79.000 144.800 79.990 ;
        RECT 82.500 78.400 92.700 79.000 ;
        RECT 82.500 68.400 83.100 78.400 ;
        RECT 87.000 77.570 88.200 78.400 ;
        RECT 83.950 77.280 91.270 77.570 ;
        RECT 83.950 69.540 84.240 77.280 ;
        RECT 87.000 75.560 88.200 77.280 ;
        RECT 85.960 75.270 89.260 75.560 ;
        RECT 85.960 71.550 86.250 75.270 ;
        RECT 87.000 71.550 88.200 75.270 ;
        RECT 88.970 71.550 89.260 75.270 ;
        RECT 85.960 71.260 89.260 71.550 ;
        RECT 87.000 69.540 88.200 71.260 ;
        RECT 90.980 69.540 91.270 77.280 ;
        RECT 83.950 69.250 91.270 69.540 ;
        RECT 87.000 68.400 88.200 69.250 ;
        RECT 92.100 68.400 92.700 78.400 ;
        RECT 82.500 67.800 92.700 68.400 ;
        RECT 96.700 78.400 106.900 79.000 ;
        RECT 96.700 68.400 97.300 78.400 ;
        RECT 101.100 77.570 102.350 78.400 ;
        RECT 98.100 77.280 105.420 77.570 ;
        RECT 98.100 69.540 98.390 77.280 ;
        RECT 101.100 75.560 102.350 77.280 ;
        RECT 100.110 75.270 103.410 75.560 ;
        RECT 100.110 71.550 100.400 75.270 ;
        RECT 101.100 72.100 102.350 75.270 ;
        RECT 103.120 71.550 103.410 75.270 ;
        RECT 100.110 71.260 103.410 71.550 ;
        RECT 105.130 69.540 105.420 77.280 ;
        RECT 98.100 69.250 105.420 69.540 ;
        RECT 106.300 68.400 106.900 78.400 ;
        RECT 96.700 67.800 106.900 68.400 ;
        RECT 110.800 78.400 121.000 79.000 ;
        RECT 110.800 68.400 111.400 78.400 ;
        RECT 117.100 77.570 118.100 77.900 ;
        RECT 112.250 77.280 119.570 77.570 ;
        RECT 112.250 69.540 112.540 77.280 ;
        RECT 117.100 76.900 118.100 77.280 ;
        RECT 117.100 75.560 118.100 75.700 ;
        RECT 114.260 75.270 118.100 75.560 ;
        RECT 114.260 71.550 114.550 75.270 ;
        RECT 117.100 74.700 118.100 75.270 ;
        RECT 115.405 72.545 116.415 74.275 ;
        RECT 117.270 71.550 117.560 74.700 ;
        RECT 114.260 71.260 117.560 71.550 ;
        RECT 119.280 69.540 119.570 77.280 ;
        RECT 112.250 69.250 119.570 69.540 ;
        RECT 120.400 68.400 121.000 78.400 ;
        RECT 110.800 67.800 121.000 68.400 ;
        RECT 125.000 78.400 135.200 79.000 ;
        RECT 125.000 68.400 125.600 78.400 ;
        RECT 129.500 77.570 130.700 78.400 ;
        RECT 126.400 77.280 133.720 77.570 ;
        RECT 126.400 69.540 126.690 77.280 ;
        RECT 129.500 75.560 130.700 77.280 ;
        RECT 128.410 75.270 131.710 75.560 ;
        RECT 128.410 71.550 128.700 75.270 ;
        RECT 129.500 72.100 130.700 75.270 ;
        RECT 131.420 71.550 131.710 75.270 ;
        RECT 128.410 71.260 131.710 71.550 ;
        RECT 133.430 69.540 133.720 77.280 ;
        RECT 126.400 69.250 133.720 69.540 ;
        RECT 134.600 68.400 135.200 78.400 ;
        RECT 125.000 67.800 135.200 68.400 ;
        RECT 139.100 78.400 149.300 79.000 ;
        RECT 139.100 68.400 139.700 78.400 ;
        RECT 143.600 77.570 144.800 78.400 ;
        RECT 140.550 77.280 147.870 77.570 ;
        RECT 140.550 69.540 140.840 77.280 ;
        RECT 143.600 75.560 144.800 77.280 ;
        RECT 142.560 75.270 145.860 75.560 ;
        RECT 142.560 71.550 142.850 75.270 ;
        RECT 143.600 71.550 144.800 75.270 ;
        RECT 145.570 71.550 145.860 75.270 ;
        RECT 142.560 71.260 145.860 71.550 ;
        RECT 143.600 69.540 144.800 71.260 ;
        RECT 147.580 69.540 147.870 77.280 ;
        RECT 140.550 69.250 147.870 69.540 ;
        RECT 143.600 68.400 144.800 69.250 ;
        RECT 148.700 68.400 149.300 78.400 ;
        RECT 139.100 67.800 149.300 68.400 ;
        RECT 87.000 63.900 88.200 67.800 ;
        RECT 143.600 63.900 144.800 67.800 ;
        RECT 82.500 63.300 135.200 63.900 ;
        RECT 82.500 53.300 83.100 63.300 ;
        RECT 87.000 62.420 88.200 63.300 ;
        RECT 83.950 62.130 91.270 62.420 ;
        RECT 83.950 54.390 84.240 62.130 ;
        RECT 87.000 60.410 88.200 62.130 ;
        RECT 85.960 60.120 89.260 60.410 ;
        RECT 85.960 56.400 86.250 60.120 ;
        RECT 87.000 56.400 88.200 60.120 ;
        RECT 88.970 56.400 89.260 60.120 ;
        RECT 85.960 56.110 89.260 56.400 ;
        RECT 87.000 54.390 88.200 56.110 ;
        RECT 90.980 54.390 91.270 62.130 ;
        RECT 83.950 54.100 91.270 54.390 ;
        RECT 87.000 53.300 88.200 54.100 ;
        RECT 92.100 53.300 92.700 63.300 ;
        RECT 82.500 52.700 92.700 53.300 ;
        RECT 96.700 53.300 97.300 63.300 ;
        RECT 98.100 62.130 105.420 62.420 ;
        RECT 98.100 54.390 98.390 62.130 ;
        RECT 100.110 60.120 103.410 60.410 ;
        RECT 100.110 56.400 100.400 60.120 ;
        RECT 101.255 59.000 102.265 59.125 ;
        RECT 101.255 58.000 102.300 59.000 ;
        RECT 101.255 57.395 102.265 58.000 ;
        RECT 103.120 57.000 103.410 60.120 ;
        RECT 102.800 56.400 103.800 57.000 ;
        RECT 100.110 56.110 103.800 56.400 ;
        RECT 102.800 56.000 103.800 56.110 ;
        RECT 105.130 55.000 105.420 62.130 ;
        RECT 104.800 54.390 105.800 55.000 ;
        RECT 98.100 54.100 105.800 54.390 ;
        RECT 104.800 54.000 105.800 54.100 ;
        RECT 106.300 53.300 106.900 63.300 ;
        RECT 96.700 52.700 106.900 53.300 ;
        RECT 110.800 53.300 111.400 63.300 ;
        RECT 112.250 62.130 119.570 62.420 ;
        RECT 112.250 55.000 112.540 62.130 ;
        RECT 114.260 60.120 117.560 60.410 ;
        RECT 114.260 57.000 114.550 60.120 ;
        RECT 115.405 59.000 116.415 59.125 ;
        RECT 115.300 58.000 116.415 59.000 ;
        RECT 115.405 57.395 116.415 58.000 ;
        RECT 113.800 56.400 114.800 57.000 ;
        RECT 117.270 56.400 117.560 60.120 ;
        RECT 113.800 56.110 117.560 56.400 ;
        RECT 113.800 56.000 114.800 56.110 ;
        RECT 112.250 54.390 113.300 55.000 ;
        RECT 119.280 54.390 119.570 62.130 ;
        RECT 112.250 54.100 119.570 54.390 ;
        RECT 112.300 54.000 113.300 54.100 ;
        RECT 120.400 53.300 121.000 63.300 ;
        RECT 110.800 52.700 121.000 53.300 ;
        RECT 125.000 53.300 125.600 63.300 ;
        RECT 126.400 62.130 133.720 62.420 ;
        RECT 126.400 55.000 126.690 62.130 ;
        RECT 128.410 60.120 131.710 60.410 ;
        RECT 128.410 57.000 128.700 60.120 ;
        RECT 129.555 59.000 130.565 59.125 ;
        RECT 129.555 58.000 130.800 59.000 ;
        RECT 129.555 57.395 130.565 58.000 ;
        RECT 128.300 56.400 129.300 57.000 ;
        RECT 131.420 56.400 131.710 60.120 ;
        RECT 128.300 56.110 131.710 56.400 ;
        RECT 128.300 56.000 129.300 56.110 ;
        RECT 126.300 54.390 127.300 55.000 ;
        RECT 133.430 54.390 133.720 62.130 ;
        RECT 126.300 54.100 133.720 54.390 ;
        RECT 126.300 54.000 127.300 54.100 ;
        RECT 134.600 53.300 135.200 63.300 ;
        RECT 125.000 52.700 135.200 53.300 ;
        RECT 139.100 63.300 149.300 63.900 ;
        RECT 139.100 53.300 139.700 63.300 ;
        RECT 143.600 62.420 144.800 63.300 ;
        RECT 140.550 62.130 147.870 62.420 ;
        RECT 140.550 54.390 140.840 62.130 ;
        RECT 143.600 60.410 144.800 62.130 ;
        RECT 142.560 60.120 145.860 60.410 ;
        RECT 142.560 56.400 142.850 60.120 ;
        RECT 143.600 56.400 144.800 60.120 ;
        RECT 145.570 56.400 145.860 60.120 ;
        RECT 142.560 56.110 145.860 56.400 ;
        RECT 143.600 54.390 144.800 56.110 ;
        RECT 147.580 54.390 147.870 62.130 ;
        RECT 140.550 54.100 147.870 54.390 ;
        RECT 143.600 53.300 144.800 54.100 ;
        RECT 148.700 53.300 149.300 63.300 ;
        RECT 139.100 52.700 149.300 53.300 ;
        RECT 87.000 48.700 88.200 52.700 ;
        RECT 143.600 48.700 144.800 52.700 ;
        RECT 82.500 48.100 135.200 48.700 ;
        RECT 82.500 38.100 83.100 48.100 ;
        RECT 87.000 47.270 88.200 48.100 ;
        RECT 83.950 46.980 91.270 47.270 ;
        RECT 83.950 39.240 84.240 46.980 ;
        RECT 87.000 45.260 88.200 46.980 ;
        RECT 85.960 44.970 89.260 45.260 ;
        RECT 85.960 41.250 86.250 44.970 ;
        RECT 87.000 41.250 88.200 44.970 ;
        RECT 88.970 41.250 89.260 44.970 ;
        RECT 85.960 40.960 89.260 41.250 ;
        RECT 87.000 39.240 88.200 40.960 ;
        RECT 90.980 39.240 91.270 46.980 ;
        RECT 83.950 38.950 91.270 39.240 ;
        RECT 87.000 38.100 88.200 38.950 ;
        RECT 92.100 38.100 92.700 48.100 ;
        RECT 82.500 37.500 92.700 38.100 ;
        RECT 96.700 38.100 97.300 48.100 ;
        RECT 98.100 46.980 105.420 47.270 ;
        RECT 98.100 39.240 98.390 46.980 ;
        RECT 100.110 44.970 103.410 45.260 ;
        RECT 100.110 41.250 100.400 44.970 ;
        RECT 101.255 43.600 102.265 43.975 ;
        RECT 103.120 43.600 103.410 44.970 ;
        RECT 105.130 43.600 105.420 46.980 ;
        RECT 101.255 42.600 102.300 43.600 ;
        RECT 102.800 42.600 103.800 43.600 ;
        RECT 104.800 42.600 105.800 43.600 ;
        RECT 101.255 42.245 102.265 42.600 ;
        RECT 103.120 41.250 103.410 42.600 ;
        RECT 100.110 40.960 103.410 41.250 ;
        RECT 105.130 39.240 105.420 42.600 ;
        RECT 98.100 38.950 105.420 39.240 ;
        RECT 106.300 38.100 106.900 48.100 ;
        RECT 96.700 37.500 106.900 38.100 ;
        RECT 110.800 38.100 111.400 48.100 ;
        RECT 115.400 47.270 116.400 47.800 ;
        RECT 112.250 46.980 119.570 47.270 ;
        RECT 112.250 39.240 112.540 46.980 ;
        RECT 115.400 46.800 116.400 46.980 ;
        RECT 115.400 45.260 116.400 45.800 ;
        RECT 114.260 44.970 117.560 45.260 ;
        RECT 114.260 41.250 114.550 44.970 ;
        RECT 115.400 44.800 116.400 44.970 ;
        RECT 115.405 42.245 116.415 43.975 ;
        RECT 117.270 41.250 117.560 44.970 ;
        RECT 114.260 40.960 117.560 41.250 ;
        RECT 119.280 39.240 119.570 46.980 ;
        RECT 112.250 38.950 119.570 39.240 ;
        RECT 120.400 38.100 121.000 48.100 ;
        RECT 110.800 37.500 121.000 38.100 ;
        RECT 125.000 38.100 125.600 48.100 ;
        RECT 126.400 46.980 133.720 47.270 ;
        RECT 126.400 43.500 126.690 46.980 ;
        RECT 128.410 44.970 131.710 45.260 ;
        RECT 128.410 43.500 128.700 44.970 ;
        RECT 129.555 43.500 130.565 43.975 ;
        RECT 126.300 42.500 127.300 43.500 ;
        RECT 128.300 42.500 129.300 43.500 ;
        RECT 129.555 42.500 130.800 43.500 ;
        RECT 126.400 39.240 126.690 42.500 ;
        RECT 128.410 41.250 128.700 42.500 ;
        RECT 129.555 42.245 130.565 42.500 ;
        RECT 131.420 41.250 131.710 44.970 ;
        RECT 128.410 40.960 131.710 41.250 ;
        RECT 133.430 39.240 133.720 46.980 ;
        RECT 126.400 38.950 133.720 39.240 ;
        RECT 134.600 38.100 135.200 48.100 ;
        RECT 125.000 37.500 135.200 38.100 ;
        RECT 139.100 48.100 149.300 48.700 ;
        RECT 139.100 38.100 139.700 48.100 ;
        RECT 143.600 47.270 144.800 48.100 ;
        RECT 140.550 46.980 147.870 47.270 ;
        RECT 140.550 39.240 140.840 46.980 ;
        RECT 143.600 45.260 144.800 46.980 ;
        RECT 142.560 44.970 145.860 45.260 ;
        RECT 142.560 41.250 142.850 44.970 ;
        RECT 143.600 41.250 144.800 44.970 ;
        RECT 145.570 41.250 145.860 44.970 ;
        RECT 142.560 40.960 145.860 41.250 ;
        RECT 143.600 39.240 144.800 40.960 ;
        RECT 147.580 39.240 147.870 46.980 ;
        RECT 140.550 38.950 147.870 39.240 ;
        RECT 143.600 38.100 144.800 38.950 ;
        RECT 148.700 38.100 149.300 48.100 ;
        RECT 139.100 37.500 149.300 38.100 ;
        RECT 87.000 33.600 88.200 37.500 ;
        RECT 143.600 33.600 144.800 37.500 ;
        RECT 82.500 33.000 135.200 33.600 ;
        RECT 82.500 23.000 83.100 33.000 ;
        RECT 87.000 32.120 88.200 33.000 ;
        RECT 83.950 31.830 91.270 32.120 ;
        RECT 83.950 24.090 84.240 31.830 ;
        RECT 87.000 30.110 88.200 31.830 ;
        RECT 85.960 29.820 89.260 30.110 ;
        RECT 85.960 26.100 86.250 29.820 ;
        RECT 87.000 26.100 88.200 29.820 ;
        RECT 88.970 26.100 89.260 29.820 ;
        RECT 85.960 25.810 89.260 26.100 ;
        RECT 87.000 24.090 88.200 25.810 ;
        RECT 90.980 24.090 91.270 31.830 ;
        RECT 83.950 23.800 91.270 24.090 ;
        RECT 87.000 23.000 88.200 23.800 ;
        RECT 92.100 23.000 92.700 33.000 ;
        RECT 82.500 22.400 92.700 23.000 ;
        RECT 96.700 23.000 97.300 33.000 ;
        RECT 104.800 32.120 105.800 32.500 ;
        RECT 98.100 31.830 105.800 32.120 ;
        RECT 98.100 24.090 98.390 31.830 ;
        RECT 104.800 31.500 105.800 31.830 ;
        RECT 102.800 30.110 103.800 30.500 ;
        RECT 100.110 29.820 103.800 30.110 ;
        RECT 100.110 26.100 100.400 29.820 ;
        RECT 102.800 29.500 103.800 29.820 ;
        RECT 101.255 28.500 102.265 28.825 ;
        RECT 101.255 27.500 102.300 28.500 ;
        RECT 101.255 27.095 102.265 27.500 ;
        RECT 103.120 26.100 103.410 29.500 ;
        RECT 100.110 25.810 103.410 26.100 ;
        RECT 105.130 24.090 105.420 31.500 ;
        RECT 98.100 23.800 105.420 24.090 ;
        RECT 106.300 23.000 106.900 33.000 ;
        RECT 96.700 22.400 106.900 23.000 ;
        RECT 110.800 23.000 111.400 33.000 ;
        RECT 115.500 32.120 116.500 32.500 ;
        RECT 112.250 31.830 119.570 32.120 ;
        RECT 112.250 24.090 112.540 31.830 ;
        RECT 115.500 31.500 116.500 31.830 ;
        RECT 115.400 30.110 116.400 30.500 ;
        RECT 114.260 29.820 117.560 30.110 ;
        RECT 114.260 26.100 114.550 29.820 ;
        RECT 115.400 29.500 116.400 29.820 ;
        RECT 115.405 28.500 116.415 28.825 ;
        RECT 115.400 27.500 116.415 28.500 ;
        RECT 115.405 27.095 116.415 27.500 ;
        RECT 117.270 26.100 117.560 29.820 ;
        RECT 114.260 25.810 117.560 26.100 ;
        RECT 119.280 24.090 119.570 31.830 ;
        RECT 112.250 23.800 119.570 24.090 ;
        RECT 120.400 23.000 121.000 33.000 ;
        RECT 110.800 22.400 121.000 23.000 ;
        RECT 125.000 23.000 125.600 33.000 ;
        RECT 126.300 32.120 127.300 32.500 ;
        RECT 126.300 31.830 133.720 32.120 ;
        RECT 126.300 31.500 127.300 31.830 ;
        RECT 126.400 24.090 126.690 31.500 ;
        RECT 128.300 30.110 129.300 30.500 ;
        RECT 128.300 29.820 131.710 30.110 ;
        RECT 128.300 29.500 129.300 29.820 ;
        RECT 128.410 26.100 128.700 29.500 ;
        RECT 129.555 28.500 130.565 28.825 ;
        RECT 129.555 27.500 130.800 28.500 ;
        RECT 129.555 27.095 130.565 27.500 ;
        RECT 131.420 26.100 131.710 29.820 ;
        RECT 128.410 25.810 131.710 26.100 ;
        RECT 133.430 24.090 133.720 31.830 ;
        RECT 126.400 23.800 133.720 24.090 ;
        RECT 134.600 23.000 135.200 33.000 ;
        RECT 125.000 22.400 135.200 23.000 ;
        RECT 139.100 33.000 149.300 33.600 ;
        RECT 139.100 23.000 139.700 33.000 ;
        RECT 143.600 32.120 144.800 33.000 ;
        RECT 140.550 31.830 147.870 32.120 ;
        RECT 140.550 24.090 140.840 31.830 ;
        RECT 143.600 30.110 144.800 31.830 ;
        RECT 142.560 29.820 145.860 30.110 ;
        RECT 142.560 26.100 142.850 29.820 ;
        RECT 143.600 26.100 144.800 29.820 ;
        RECT 145.570 26.100 145.860 29.820 ;
        RECT 142.560 25.810 145.860 26.100 ;
        RECT 143.600 24.090 144.800 25.810 ;
        RECT 147.580 24.090 147.870 31.830 ;
        RECT 140.550 23.800 147.870 24.090 ;
        RECT 143.600 23.000 144.800 23.800 ;
        RECT 148.700 23.000 149.300 33.000 ;
        RECT 139.100 22.400 149.300 23.000 ;
        RECT 87.000 18.400 88.200 22.400 ;
        RECT 143.600 18.400 144.800 22.400 ;
        RECT 82.500 17.800 92.700 18.400 ;
        RECT 82.500 7.800 83.100 17.800 ;
        RECT 87.000 16.970 88.200 17.800 ;
        RECT 83.950 16.680 91.270 16.970 ;
        RECT 83.950 8.940 84.240 16.680 ;
        RECT 87.000 14.960 88.200 16.680 ;
        RECT 85.960 14.670 89.260 14.960 ;
        RECT 85.960 10.950 86.250 14.670 ;
        RECT 87.000 10.950 88.200 14.670 ;
        RECT 88.970 10.950 89.260 14.670 ;
        RECT 85.960 10.660 89.260 10.950 ;
        RECT 87.000 8.940 88.200 10.660 ;
        RECT 90.980 8.940 91.270 16.680 ;
        RECT 83.950 8.650 91.270 8.940 ;
        RECT 87.000 7.800 88.200 8.650 ;
        RECT 92.100 7.800 92.700 17.800 ;
        RECT 82.500 7.200 92.700 7.800 ;
        RECT 96.700 17.800 106.900 18.400 ;
        RECT 96.700 7.800 97.300 17.800 ;
        RECT 98.100 16.680 105.420 16.970 ;
        RECT 98.100 8.940 98.390 16.680 ;
        RECT 100.110 14.670 103.410 14.960 ;
        RECT 100.110 10.950 100.400 14.670 ;
        RECT 101.200 10.950 102.400 13.900 ;
        RECT 103.120 10.950 103.410 14.670 ;
        RECT 100.110 10.660 103.410 10.950 ;
        RECT 101.200 8.940 102.400 10.660 ;
        RECT 105.130 8.940 105.420 16.680 ;
        RECT 98.100 8.650 105.420 8.940 ;
        RECT 101.200 7.800 102.400 8.650 ;
        RECT 106.300 7.800 106.900 17.800 ;
        RECT 96.700 7.200 106.900 7.800 ;
        RECT 110.800 17.800 121.000 18.400 ;
        RECT 110.800 7.800 111.400 17.800 ;
        RECT 112.250 16.680 119.570 16.970 ;
        RECT 112.250 8.940 112.540 16.680 ;
        RECT 114.260 14.670 117.560 14.960 ;
        RECT 114.260 10.950 114.550 14.670 ;
        RECT 115.300 10.950 116.500 13.900 ;
        RECT 117.270 10.950 117.560 14.670 ;
        RECT 114.260 10.660 117.560 10.950 ;
        RECT 115.300 8.940 116.500 10.660 ;
        RECT 119.280 8.940 119.570 16.680 ;
        RECT 112.250 8.650 119.570 8.940 ;
        RECT 115.300 7.800 116.500 8.650 ;
        RECT 120.400 7.800 121.000 17.800 ;
        RECT 110.800 7.200 121.000 7.800 ;
        RECT 125.000 17.800 135.200 18.400 ;
        RECT 125.000 7.800 125.600 17.800 ;
        RECT 126.400 16.680 133.720 16.970 ;
        RECT 126.400 8.940 126.690 16.680 ;
        RECT 128.410 14.670 131.710 14.960 ;
        RECT 128.410 10.950 128.700 14.670 ;
        RECT 129.400 10.950 130.600 13.900 ;
        RECT 131.420 10.950 131.710 14.670 ;
        RECT 128.410 10.660 131.710 10.950 ;
        RECT 129.400 8.940 130.600 10.660 ;
        RECT 133.430 8.940 133.720 16.680 ;
        RECT 126.400 8.650 133.720 8.940 ;
        RECT 129.400 7.800 130.600 8.650 ;
        RECT 134.600 7.800 135.200 17.800 ;
        RECT 125.000 7.200 135.200 7.800 ;
        RECT 139.100 17.800 149.300 18.400 ;
        RECT 139.100 7.800 139.700 17.800 ;
        RECT 143.600 16.970 144.800 17.800 ;
        RECT 140.550 16.680 147.870 16.970 ;
        RECT 140.550 8.940 140.840 16.680 ;
        RECT 143.600 14.960 144.800 16.680 ;
        RECT 142.560 14.670 145.860 14.960 ;
        RECT 142.560 10.950 142.850 14.670 ;
        RECT 143.600 10.950 144.800 14.670 ;
        RECT 145.570 10.950 145.860 14.670 ;
        RECT 142.560 10.660 145.860 10.950 ;
        RECT 143.600 8.940 144.800 10.660 ;
        RECT 147.580 8.940 147.870 16.680 ;
        RECT 140.550 8.650 147.870 8.940 ;
        RECT 143.600 7.800 144.800 8.650 ;
        RECT 148.700 7.800 149.300 17.800 ;
        RECT 139.100 7.200 149.300 7.800 ;
        RECT 87.000 5.000 88.200 7.200 ;
        RECT 101.200 6.000 102.400 7.200 ;
        RECT 115.300 6.000 116.500 7.200 ;
        RECT 129.400 6.000 130.600 7.200 ;
        RECT 143.600 6.000 144.800 7.200 ;
        RECT 101.200 5.000 144.800 6.000 ;
      LAYER met2 ;
        RECT 99.300 102.100 100.900 103.600 ;
        RECT 131.300 92.300 132.300 95.350 ;
        RECT 105.850 90.850 115.450 91.400 ;
        RECT 105.850 87.200 106.400 90.850 ;
        RECT 119.500 90.300 119.900 92.200 ;
        RECT 131.300 90.550 131.700 92.300 ;
        RECT 122.450 90.150 131.700 90.550 ;
        RECT 122.450 89.900 122.850 90.150 ;
        RECT 107.050 89.500 122.850 89.900 ;
        RECT 147.250 89.700 148.250 94.950 ;
        RECT 107.050 88.600 107.450 89.500 ;
        RECT 124.300 88.700 148.250 89.700 ;
        RECT 109.700 87.700 125.300 88.700 ;
        RECT 109.700 86.700 110.700 87.700 ;
        RECT 93.000 85.700 110.700 86.700 ;
        RECT 115.400 73.000 116.400 87.700 ;
        RECT 131.200 86.100 132.300 86.300 ;
        RECT 117.100 85.300 132.300 86.100 ;
        RECT 117.100 85.100 131.200 85.300 ;
        RECT 122.800 83.800 129.300 84.800 ;
        RECT 147.250 83.300 148.250 88.700 ;
        RECT 117.100 74.700 118.100 82.800 ;
        RECT 101.300 58.000 116.300 59.000 ;
        RECT 101.300 28.500 102.300 58.000 ;
        RECT 102.800 56.000 114.800 57.000 ;
        RECT 102.800 30.500 103.800 56.000 ;
        RECT 104.800 54.000 113.300 55.000 ;
        RECT 104.800 32.500 105.800 54.000 ;
        RECT 121.300 47.800 122.300 82.800 ;
        RECT 115.400 46.800 122.300 47.800 ;
        RECT 122.800 45.800 123.800 82.800 ;
        RECT 115.400 44.800 123.800 45.800 ;
        RECT 124.300 43.600 125.300 82.800 ;
        RECT 115.400 42.600 125.300 43.600 ;
        RECT 126.300 32.500 127.300 82.800 ;
        RECT 104.800 31.500 127.300 32.500 ;
        RECT 128.300 30.500 129.300 82.800 ;
        RECT 102.800 29.500 129.300 30.500 ;
        RECT 129.800 28.500 130.800 82.800 ;
        RECT 132.900 80.000 147.100 81.000 ;
        RECT 101.300 27.500 130.800 28.500 ;
      LAYER met3 ;
        RECT 37.200 102.100 48.900 103.600 ;
        RECT 99.300 102.100 100.900 103.600 ;
        RECT 131.300 94.350 132.300 95.350 ;
        RECT 93.000 85.700 94.100 86.700 ;
        RECT 133.450 81.500 147.850 104.360 ;
        RECT 132.900 80.000 147.100 81.000 ;
      LAYER met4 ;
        RECT 29.000 102.100 38.700 103.600 ;
        RECT 47.400 102.100 100.900 103.600 ;
        RECT 133.845 95.350 147.455 103.965 ;
        RECT 131.300 94.350 147.455 95.350 ;
        RECT 133.845 88.900 147.455 94.350 ;
        RECT 133.845 88.000 152.700 88.900 ;
        RECT 43.000 85.700 94.100 86.700 ;
        RECT 133.845 83.355 147.455 88.000 ;
        RECT 132.900 80.000 147.850 82.000 ;
        RECT 151.800 1.000 152.700 88.000 ;
        RECT 151.800 0.000 151.810 1.000 ;
  END
END tt_um_ik_0_ptat_bgr
END LIBRARY

